VERSION 5.7 ;
  NOWIREEXTENSIONATPIN ON ;
  DIVIDERCHAR "/" ;
  BUSBITCHARS "[]" ;
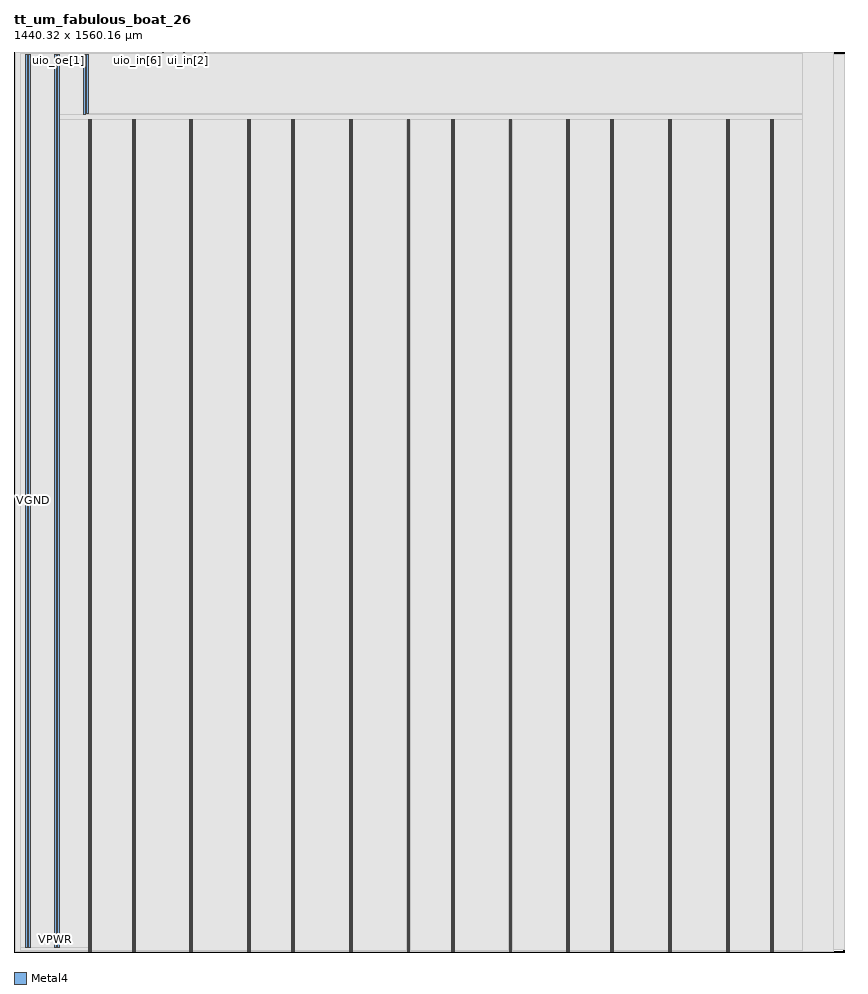
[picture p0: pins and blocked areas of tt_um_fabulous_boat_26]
MACRO tt_um_fabulous_boat_26
  CLASS BLOCK ;
  FOREIGN tt_um_fabulous_boat_26 ;
  ORIGIN 0.000 0.000 ;
  SIZE 1440.320 BY 1560.160 ;
  PIN VGND
    DIRECTION INOUT ;
    USE GROUND ;
    PORT
      LAYER Metal4 ;
        RECT 132.580 1368.760 134.180 1443.240 ;
    END
    PORT
      LAYER Metal4 ;
        RECT 132.580 1110.040 134.180 1368.760 ;
    END
    PORT
      LAYER Metal4 ;
        RECT 132.580 851.320 134.180 1110.040 ;
    END
    PORT
      LAYER Metal4 ;
        RECT 132.580 592.600 134.180 851.320 ;
    END
    PORT
      LAYER Metal4 ;
        RECT 132.580 333.880 134.180 592.600 ;
    END
    PORT
      LAYER Metal4 ;
        RECT 132.580 75.160 134.180 333.880 ;
    END
    PORT
      LAYER Metal4 ;
        RECT 132.580 0.680 134.180 75.160 ;
    END
    PORT
      LAYER Metal4 ;
        RECT 208.180 1368.760 209.780 1443.240 ;
    END
    PORT
      LAYER Metal4 ;
        RECT 308.180 1368.760 309.780 1443.240 ;
    END
    PORT
      LAYER Metal4 ;
        RECT 408.180 1368.760 409.780 1443.240 ;
    END
    PORT
      LAYER Metal4 ;
        RECT 208.180 1110.040 209.780 1368.760 ;
    END
    PORT
      LAYER Metal4 ;
        RECT 308.180 1110.040 309.780 1368.760 ;
    END
    PORT
      LAYER Metal4 ;
        RECT 408.180 1110.040 409.780 1368.760 ;
    END
    PORT
      LAYER Metal4 ;
        RECT 208.180 851.320 209.780 1110.040 ;
    END
    PORT
      LAYER Metal4 ;
        RECT 308.180 851.320 309.780 1110.040 ;
    END
    PORT
      LAYER Metal4 ;
        RECT 408.180 851.320 409.780 1110.040 ;
    END
    PORT
      LAYER Metal4 ;
        RECT 208.180 592.600 209.780 851.320 ;
    END
    PORT
      LAYER Metal4 ;
        RECT 308.180 592.600 309.780 851.320 ;
    END
    PORT
      LAYER Metal4 ;
        RECT 408.180 592.600 409.780 851.320 ;
    END
    PORT
      LAYER Metal4 ;
        RECT 208.180 333.880 209.780 592.600 ;
    END
    PORT
      LAYER Metal4 ;
        RECT 308.180 333.880 309.780 592.600 ;
    END
    PORT
      LAYER Metal4 ;
        RECT 408.180 333.880 409.780 592.600 ;
    END
    PORT
      LAYER Metal4 ;
        RECT 208.180 75.160 209.780 333.880 ;
    END
    PORT
      LAYER Metal4 ;
        RECT 308.180 75.160 309.780 333.880 ;
    END
    PORT
      LAYER Metal4 ;
        RECT 408.180 75.160 409.780 333.880 ;
    END
    PORT
      LAYER Metal4 ;
        RECT 208.180 0.680 209.780 75.160 ;
    END
    PORT
      LAYER Metal4 ;
        RECT 308.180 0.680 309.780 75.160 ;
    END
    PORT
      LAYER Metal4 ;
        RECT 408.180 0.680 409.780 75.160 ;
    END
    PORT
      LAYER Metal4 ;
        RECT 484.820 1368.760 486.420 1443.240 ;
    END
    PORT
      LAYER Metal4 ;
        RECT 584.820 1368.760 586.420 1443.240 ;
    END
    PORT
      LAYER Metal4 ;
        RECT 684.820 1368.760 686.420 1443.240 ;
    END
    PORT
      LAYER Metal4 ;
        RECT 484.820 1110.040 486.420 1368.760 ;
    END
    PORT
      LAYER Metal4 ;
        RECT 584.820 1110.040 586.420 1368.760 ;
    END
    PORT
      LAYER Metal4 ;
        RECT 684.820 1110.040 686.420 1368.760 ;
    END
    PORT
      LAYER Metal4 ;
        RECT 484.820 851.320 486.420 1110.040 ;
    END
    PORT
      LAYER Metal4 ;
        RECT 584.820 851.320 586.420 1110.040 ;
    END
    PORT
      LAYER Metal4 ;
        RECT 684.820 851.320 686.420 1110.040 ;
    END
    PORT
      LAYER Metal4 ;
        RECT 484.820 592.600 486.420 851.320 ;
    END
    PORT
      LAYER Metal4 ;
        RECT 584.820 592.600 586.420 851.320 ;
    END
    PORT
      LAYER Metal4 ;
        RECT 684.820 592.600 686.420 851.320 ;
    END
    PORT
      LAYER Metal4 ;
        RECT 484.820 333.880 486.420 592.600 ;
    END
    PORT
      LAYER Metal4 ;
        RECT 584.820 333.880 586.420 592.600 ;
    END
    PORT
      LAYER Metal4 ;
        RECT 684.820 333.880 686.420 592.600 ;
    END
    PORT
      LAYER Metal4 ;
        RECT 484.820 75.160 486.420 333.880 ;
    END
    PORT
      LAYER Metal4 ;
        RECT 584.820 75.160 586.420 333.880 ;
    END
    PORT
      LAYER Metal4 ;
        RECT 684.820 75.160 686.420 333.880 ;
    END
    PORT
      LAYER Metal4 ;
        RECT 484.820 0.680 486.420 75.160 ;
    END
    PORT
      LAYER Metal4 ;
        RECT 584.820 0.680 586.420 75.160 ;
    END
    PORT
      LAYER Metal4 ;
        RECT 684.820 0.680 686.420 75.160 ;
    END
    PORT
      LAYER Metal4 ;
        RECT 761.460 1368.760 763.060 1443.240 ;
    END
    PORT
      LAYER Metal4 ;
        RECT 861.460 1368.760 863.060 1443.240 ;
    END
    PORT
      LAYER Metal4 ;
        RECT 961.460 1368.760 963.060 1443.240 ;
    END
    PORT
      LAYER Metal4 ;
        RECT 761.460 1110.040 763.060 1368.760 ;
    END
    PORT
      LAYER Metal4 ;
        RECT 861.460 1110.040 863.060 1368.760 ;
    END
    PORT
      LAYER Metal4 ;
        RECT 961.460 1110.040 963.060 1368.760 ;
    END
    PORT
      LAYER Metal4 ;
        RECT 761.460 851.320 763.060 1110.040 ;
    END
    PORT
      LAYER Metal4 ;
        RECT 861.460 851.320 863.060 1110.040 ;
    END
    PORT
      LAYER Metal4 ;
        RECT 961.460 851.320 963.060 1110.040 ;
    END
    PORT
      LAYER Metal4 ;
        RECT 761.460 592.600 763.060 851.320 ;
    END
    PORT
      LAYER Metal4 ;
        RECT 861.460 592.600 863.060 851.320 ;
    END
    PORT
      LAYER Metal4 ;
        RECT 961.460 592.600 963.060 851.320 ;
    END
    PORT
      LAYER Metal4 ;
        RECT 761.460 333.880 763.060 592.600 ;
    END
    PORT
      LAYER Metal4 ;
        RECT 861.460 333.880 863.060 592.600 ;
    END
    PORT
      LAYER Metal4 ;
        RECT 961.460 333.880 963.060 592.600 ;
    END
    PORT
      LAYER Metal4 ;
        RECT 761.460 75.160 763.060 333.880 ;
    END
    PORT
      LAYER Metal4 ;
        RECT 861.460 75.160 863.060 333.880 ;
    END
    PORT
      LAYER Metal4 ;
        RECT 961.460 75.160 963.060 333.880 ;
    END
    PORT
      LAYER Metal4 ;
        RECT 761.460 0.680 763.060 75.160 ;
    END
    PORT
      LAYER Metal4 ;
        RECT 861.460 0.680 863.060 75.160 ;
    END
    PORT
      LAYER Metal4 ;
        RECT 961.460 0.680 963.060 75.160 ;
    END
    PORT
      LAYER Metal4 ;
        RECT 1038.100 1368.760 1039.700 1443.240 ;
    END
    PORT
      LAYER Metal4 ;
        RECT 1138.100 1368.760 1139.700 1443.240 ;
    END
    PORT
      LAYER Metal4 ;
        RECT 1238.100 1368.760 1239.700 1443.240 ;
    END
    PORT
      LAYER Metal4 ;
        RECT 1038.100 1110.040 1039.700 1368.760 ;
    END
    PORT
      LAYER Metal4 ;
        RECT 1138.100 1110.040 1139.700 1368.760 ;
    END
    PORT
      LAYER Metal4 ;
        RECT 1238.100 1110.040 1239.700 1368.760 ;
    END
    PORT
      LAYER Metal4 ;
        RECT 1038.100 851.320 1039.700 1110.040 ;
    END
    PORT
      LAYER Metal4 ;
        RECT 1138.100 851.320 1139.700 1110.040 ;
    END
    PORT
      LAYER Metal4 ;
        RECT 1238.100 851.320 1239.700 1110.040 ;
    END
    PORT
      LAYER Metal4 ;
        RECT 1038.100 592.600 1039.700 851.320 ;
    END
    PORT
      LAYER Metal4 ;
        RECT 1138.100 592.600 1139.700 851.320 ;
    END
    PORT
      LAYER Metal4 ;
        RECT 1238.100 592.600 1239.700 851.320 ;
    END
    PORT
      LAYER Metal4 ;
        RECT 1038.100 333.880 1039.700 592.600 ;
    END
    PORT
      LAYER Metal4 ;
        RECT 1138.100 333.880 1139.700 592.600 ;
    END
    PORT
      LAYER Metal4 ;
        RECT 1238.100 333.880 1239.700 592.600 ;
    END
    PORT
      LAYER Metal4 ;
        RECT 1038.100 75.160 1039.700 333.880 ;
    END
    PORT
      LAYER Metal4 ;
        RECT 1138.100 75.160 1139.700 333.880 ;
    END
    PORT
      LAYER Metal4 ;
        RECT 1238.100 75.160 1239.700 333.880 ;
    END
    PORT
      LAYER Metal4 ;
        RECT 1038.100 0.680 1039.700 75.160 ;
    END
    PORT
      LAYER Metal4 ;
        RECT 1138.100 0.680 1139.700 75.160 ;
    END
    PORT
      LAYER Metal4 ;
        RECT 1238.100 0.680 1239.700 75.160 ;
    END
    PORT
      LAYER Metal4 ;
        RECT 1314.740 1368.760 1316.340 1443.240 ;
    END
    PORT
      LAYER Metal4 ;
        RECT 1314.740 1110.040 1316.340 1368.760 ;
    END
    PORT
      LAYER Metal4 ;
        RECT 1314.740 851.320 1316.340 1110.040 ;
    END
    PORT
      LAYER Metal4 ;
        RECT 1314.740 592.600 1316.340 851.320 ;
    END
    PORT
      LAYER Metal4 ;
        RECT 1314.740 333.880 1316.340 592.600 ;
    END
    PORT
      LAYER Metal4 ;
        RECT 1314.740 75.160 1316.340 333.880 ;
    END
    PORT
      LAYER Metal4 ;
        RECT 1314.740 0.680 1316.340 75.160 ;
    END
    PORT
      LAYER Metal4 ;
        RECT 25.540 7.540 28.740 1556.540 ;
    END
    PORT
      LAYER Metal4 ;
        RECT 75.540 7.540 78.740 1556.540 ;
    END
    PORT
      LAYER Metal4 ;
        RECT 125.540 1453.800 128.740 1556.540 ;
    END
  END VGND
  PIN VPWR
    DIRECTION INOUT ;
    USE POWER ;
    PORT
      LAYER Metal4 ;
        RECT 129.280 1368.760 130.880 1443.240 ;
    END
    PORT
      LAYER Metal4 ;
        RECT 129.280 1110.040 130.880 1368.760 ;
    END
    PORT
      LAYER Metal4 ;
        RECT 129.280 851.320 130.880 1110.040 ;
    END
    PORT
      LAYER Metal4 ;
        RECT 129.280 592.600 130.880 851.320 ;
    END
    PORT
      LAYER Metal4 ;
        RECT 129.280 333.880 130.880 592.600 ;
    END
    PORT
      LAYER Metal4 ;
        RECT 129.280 75.160 130.880 333.880 ;
    END
    PORT
      LAYER Metal4 ;
        RECT 129.280 0.680 130.880 75.160 ;
    END
    PORT
      LAYER Metal4 ;
        RECT 204.880 1368.760 206.480 1443.240 ;
    END
    PORT
      LAYER Metal4 ;
        RECT 304.880 1368.760 306.480 1443.240 ;
    END
    PORT
      LAYER Metal4 ;
        RECT 404.880 1368.760 406.480 1443.240 ;
    END
    PORT
      LAYER Metal4 ;
        RECT 204.880 1110.040 206.480 1368.760 ;
    END
    PORT
      LAYER Metal4 ;
        RECT 304.880 1110.040 306.480 1368.760 ;
    END
    PORT
      LAYER Metal4 ;
        RECT 404.880 1110.040 406.480 1368.760 ;
    END
    PORT
      LAYER Metal4 ;
        RECT 204.880 851.320 206.480 1110.040 ;
    END
    PORT
      LAYER Metal4 ;
        RECT 304.880 851.320 306.480 1110.040 ;
    END
    PORT
      LAYER Metal4 ;
        RECT 404.880 851.320 406.480 1110.040 ;
    END
    PORT
      LAYER Metal4 ;
        RECT 204.880 592.600 206.480 851.320 ;
    END
    PORT
      LAYER Metal4 ;
        RECT 304.880 592.600 306.480 851.320 ;
    END
    PORT
      LAYER Metal4 ;
        RECT 404.880 592.600 406.480 851.320 ;
    END
    PORT
      LAYER Metal4 ;
        RECT 204.880 333.880 206.480 592.600 ;
    END
    PORT
      LAYER Metal4 ;
        RECT 304.880 333.880 306.480 592.600 ;
    END
    PORT
      LAYER Metal4 ;
        RECT 404.880 333.880 406.480 592.600 ;
    END
    PORT
      LAYER Metal4 ;
        RECT 204.880 75.160 206.480 333.880 ;
    END
    PORT
      LAYER Metal4 ;
        RECT 304.880 75.160 306.480 333.880 ;
    END
    PORT
      LAYER Metal4 ;
        RECT 404.880 75.160 406.480 333.880 ;
    END
    PORT
      LAYER Metal4 ;
        RECT 204.880 0.680 206.480 75.160 ;
    END
    PORT
      LAYER Metal4 ;
        RECT 304.880 0.680 306.480 75.160 ;
    END
    PORT
      LAYER Metal4 ;
        RECT 404.880 0.680 406.480 75.160 ;
    END
    PORT
      LAYER Metal4 ;
        RECT 481.520 1368.760 483.120 1443.240 ;
    END
    PORT
      LAYER Metal4 ;
        RECT 581.520 1368.760 583.120 1443.240 ;
    END
    PORT
      LAYER Metal4 ;
        RECT 681.520 1368.760 683.120 1443.240 ;
    END
    PORT
      LAYER Metal4 ;
        RECT 481.520 1110.040 483.120 1368.760 ;
    END
    PORT
      LAYER Metal4 ;
        RECT 581.520 1110.040 583.120 1368.760 ;
    END
    PORT
      LAYER Metal4 ;
        RECT 681.520 1110.040 683.120 1368.760 ;
    END
    PORT
      LAYER Metal4 ;
        RECT 481.520 851.320 483.120 1110.040 ;
    END
    PORT
      LAYER Metal4 ;
        RECT 581.520 851.320 583.120 1110.040 ;
    END
    PORT
      LAYER Metal4 ;
        RECT 681.520 851.320 683.120 1110.040 ;
    END
    PORT
      LAYER Metal4 ;
        RECT 481.520 592.600 483.120 851.320 ;
    END
    PORT
      LAYER Metal4 ;
        RECT 581.520 592.600 583.120 851.320 ;
    END
    PORT
      LAYER Metal4 ;
        RECT 681.520 592.600 683.120 851.320 ;
    END
    PORT
      LAYER Metal4 ;
        RECT 481.520 333.880 483.120 592.600 ;
    END
    PORT
      LAYER Metal4 ;
        RECT 581.520 333.880 583.120 592.600 ;
    END
    PORT
      LAYER Metal4 ;
        RECT 681.520 333.880 683.120 592.600 ;
    END
    PORT
      LAYER Metal4 ;
        RECT 481.520 75.160 483.120 333.880 ;
    END
    PORT
      LAYER Metal4 ;
        RECT 581.520 75.160 583.120 333.880 ;
    END
    PORT
      LAYER Metal4 ;
        RECT 681.520 75.160 683.120 333.880 ;
    END
    PORT
      LAYER Metal4 ;
        RECT 481.520 0.680 483.120 75.160 ;
    END
    PORT
      LAYER Metal4 ;
        RECT 581.520 0.680 583.120 75.160 ;
    END
    PORT
      LAYER Metal4 ;
        RECT 681.520 0.680 683.120 75.160 ;
    END
    PORT
      LAYER Metal4 ;
        RECT 758.160 1368.760 759.760 1443.240 ;
    END
    PORT
      LAYER Metal4 ;
        RECT 858.160 1368.760 859.760 1443.240 ;
    END
    PORT
      LAYER Metal4 ;
        RECT 958.160 1368.760 959.760 1443.240 ;
    END
    PORT
      LAYER Metal4 ;
        RECT 758.160 1110.040 759.760 1368.760 ;
    END
    PORT
      LAYER Metal4 ;
        RECT 858.160 1110.040 859.760 1368.760 ;
    END
    PORT
      LAYER Metal4 ;
        RECT 958.160 1110.040 959.760 1368.760 ;
    END
    PORT
      LAYER Metal4 ;
        RECT 758.160 851.320 759.760 1110.040 ;
    END
    PORT
      LAYER Metal4 ;
        RECT 858.160 851.320 859.760 1110.040 ;
    END
    PORT
      LAYER Metal4 ;
        RECT 958.160 851.320 959.760 1110.040 ;
    END
    PORT
      LAYER Metal4 ;
        RECT 758.160 592.600 759.760 851.320 ;
    END
    PORT
      LAYER Metal4 ;
        RECT 858.160 592.600 859.760 851.320 ;
    END
    PORT
      LAYER Metal4 ;
        RECT 958.160 592.600 959.760 851.320 ;
    END
    PORT
      LAYER Metal4 ;
        RECT 758.160 333.880 759.760 592.600 ;
    END
    PORT
      LAYER Metal4 ;
        RECT 858.160 333.880 859.760 592.600 ;
    END
    PORT
      LAYER Metal4 ;
        RECT 958.160 333.880 959.760 592.600 ;
    END
    PORT
      LAYER Metal4 ;
        RECT 758.160 75.160 759.760 333.880 ;
    END
    PORT
      LAYER Metal4 ;
        RECT 858.160 75.160 859.760 333.880 ;
    END
    PORT
      LAYER Metal4 ;
        RECT 958.160 75.160 959.760 333.880 ;
    END
    PORT
      LAYER Metal4 ;
        RECT 758.160 0.680 759.760 75.160 ;
    END
    PORT
      LAYER Metal4 ;
        RECT 858.160 0.680 859.760 75.160 ;
    END
    PORT
      LAYER Metal4 ;
        RECT 958.160 0.680 959.760 75.160 ;
    END
    PORT
      LAYER Metal4 ;
        RECT 1034.800 1368.760 1036.400 1443.240 ;
    END
    PORT
      LAYER Metal4 ;
        RECT 1134.800 1368.760 1136.400 1443.240 ;
    END
    PORT
      LAYER Metal4 ;
        RECT 1234.800 1368.760 1236.400 1443.240 ;
    END
    PORT
      LAYER Metal4 ;
        RECT 1034.800 1110.040 1036.400 1368.760 ;
    END
    PORT
      LAYER Metal4 ;
        RECT 1134.800 1110.040 1136.400 1368.760 ;
    END
    PORT
      LAYER Metal4 ;
        RECT 1234.800 1110.040 1236.400 1368.760 ;
    END
    PORT
      LAYER Metal4 ;
        RECT 1034.800 851.320 1036.400 1110.040 ;
    END
    PORT
      LAYER Metal4 ;
        RECT 1134.800 851.320 1136.400 1110.040 ;
    END
    PORT
      LAYER Metal4 ;
        RECT 1234.800 851.320 1236.400 1110.040 ;
    END
    PORT
      LAYER Metal4 ;
        RECT 1034.800 592.600 1036.400 851.320 ;
    END
    PORT
      LAYER Metal4 ;
        RECT 1134.800 592.600 1136.400 851.320 ;
    END
    PORT
      LAYER Metal4 ;
        RECT 1234.800 592.600 1236.400 851.320 ;
    END
    PORT
      LAYER Metal4 ;
        RECT 1034.800 333.880 1036.400 592.600 ;
    END
    PORT
      LAYER Metal4 ;
        RECT 1134.800 333.880 1136.400 592.600 ;
    END
    PORT
      LAYER Metal4 ;
        RECT 1234.800 333.880 1236.400 592.600 ;
    END
    PORT
      LAYER Metal4 ;
        RECT 1034.800 75.160 1036.400 333.880 ;
    END
    PORT
      LAYER Metal4 ;
        RECT 1134.800 75.160 1136.400 333.880 ;
    END
    PORT
      LAYER Metal4 ;
        RECT 1234.800 75.160 1236.400 333.880 ;
    END
    PORT
      LAYER Metal4 ;
        RECT 1034.800 0.680 1036.400 75.160 ;
    END
    PORT
      LAYER Metal4 ;
        RECT 1134.800 0.680 1136.400 75.160 ;
    END
    PORT
      LAYER Metal4 ;
        RECT 1234.800 0.680 1236.400 75.160 ;
    END
    PORT
      LAYER Metal4 ;
        RECT 1311.440 1368.760 1313.040 1443.240 ;
    END
    PORT
      LAYER Metal4 ;
        RECT 1311.440 1110.040 1313.040 1368.760 ;
    END
    PORT
      LAYER Metal4 ;
        RECT 1311.440 851.320 1313.040 1110.040 ;
    END
    PORT
      LAYER Metal4 ;
        RECT 1311.440 592.600 1313.040 851.320 ;
    END
    PORT
      LAYER Metal4 ;
        RECT 1311.440 333.880 1313.040 592.600 ;
    END
    PORT
      LAYER Metal4 ;
        RECT 1311.440 75.160 1313.040 333.880 ;
    END
    PORT
      LAYER Metal4 ;
        RECT 1311.440 0.680 1313.040 75.160 ;
    END
    PORT
      LAYER Metal4 ;
        RECT 20.640 7.540 23.840 1556.540 ;
    END
    PORT
      LAYER Metal4 ;
        RECT 70.640 7.540 73.840 1556.540 ;
    END
    PORT
      LAYER Metal4 ;
        RECT 120.640 1452.310 123.840 1556.540 ;
    END
  END VPWR
  PIN clk
    DIRECTION INPUT ;
    USE SIGNAL ;
    ANTENNAGATEAREA 4.704000 ;
    ANTENNADIFFAREA 0.877000 ;
    PORT
      LAYER Metal4 ;
        RECT 331.090 1559.160 331.390 1560.160 ;
    END
  END clk
  PIN ena
    DIRECTION INPUT ;
    USE SIGNAL ;
    PORT
      LAYER Metal4 ;
        RECT 338.370 1559.160 338.670 1560.160 ;
    END
  END ena
  PIN rst_n
    DIRECTION INPUT ;
    USE SIGNAL ;
    ANTENNAGATEAREA 0.666400 ;
    ANTENNADIFFAREA 0.438500 ;
    PORT
      LAYER Metal4 ;
        RECT 323.810 1559.160 324.110 1560.160 ;
    END
  END rst_n
  PIN ui_in[0]
    DIRECTION INPUT ;
    USE SIGNAL ;
    ANTENNAGATEAREA 0.666400 ;
    ANTENNADIFFAREA 0.438500 ;
    PORT
      LAYER Metal4 ;
        RECT 316.530 1559.160 316.830 1560.160 ;
    END
  END ui_in[0]
  PIN ui_in[1]
    DIRECTION INPUT ;
    USE SIGNAL ;
    ANTENNAGATEAREA 0.666400 ;
    ANTENNADIFFAREA 0.438500 ;
    PORT
      LAYER Metal4 ;
        RECT 309.250 1559.160 309.550 1560.160 ;
    END
  END ui_in[1]
  PIN ui_in[2]
    DIRECTION INPUT ;
    USE SIGNAL ;
    ANTENNAGATEAREA 1.764000 ;
    ANTENNADIFFAREA 0.438500 ;
    PORT
      LAYER Metal4 ;
        RECT 301.970 1559.160 302.270 1560.160 ;
    END
  END ui_in[2]
  PIN ui_in[3]
    DIRECTION INPUT ;
    USE SIGNAL ;
    ANTENNAGATEAREA 1.764000 ;
    ANTENNADIFFAREA 0.438500 ;
    PORT
      LAYER Metal4 ;
        RECT 294.690 1559.160 294.990 1560.160 ;
    END
  END ui_in[3]
  PIN ui_in[4]
    DIRECTION INPUT ;
    USE SIGNAL ;
    ANTENNAGATEAREA 1.764000 ;
    ANTENNADIFFAREA 0.438500 ;
    PORT
      LAYER Metal4 ;
        RECT 287.410 1559.160 287.710 1560.160 ;
    END
  END ui_in[4]
  PIN ui_in[5]
    DIRECTION INPUT ;
    USE SIGNAL ;
    ANTENNAGATEAREA 1.764000 ;
    ANTENNADIFFAREA 0.438500 ;
    PORT
      LAYER Metal4 ;
        RECT 280.130 1559.160 280.430 1560.160 ;
    END
  END ui_in[5]
  PIN ui_in[6]
    DIRECTION INPUT ;
    USE SIGNAL ;
    ANTENNAGATEAREA 1.764000 ;
    ANTENNADIFFAREA 0.438500 ;
    PORT
      LAYER Metal4 ;
        RECT 272.850 1559.160 273.150 1560.160 ;
    END
  END ui_in[6]
  PIN ui_in[7]
    DIRECTION INPUT ;
    USE SIGNAL ;
    ANTENNAGATEAREA 1.764000 ;
    ANTENNADIFFAREA 0.438500 ;
    PORT
      LAYER Metal4 ;
        RECT 265.570 1559.160 265.870 1560.160 ;
    END
  END ui_in[7]
  PIN uio_in[0]
    DIRECTION INPUT ;
    USE SIGNAL ;
    ANTENNAGATEAREA 1.332800 ;
    ANTENNADIFFAREA 0.438500 ;
    PORT
      LAYER Metal4 ;
        RECT 258.290 1559.160 258.590 1560.160 ;
    END
  END uio_in[0]
  PIN uio_in[1]
    DIRECTION INPUT ;
    USE SIGNAL ;
    ANTENNAGATEAREA 1.332800 ;
    ANTENNADIFFAREA 0.438500 ;
    PORT
      LAYER Metal4 ;
        RECT 251.010 1559.160 251.310 1560.160 ;
    END
  END uio_in[1]
  PIN uio_in[2]
    DIRECTION INPUT ;
    USE SIGNAL ;
    ANTENNAGATEAREA 1.332800 ;
    ANTENNADIFFAREA 0.438500 ;
    PORT
      LAYER Metal4 ;
        RECT 243.730 1559.160 244.030 1560.160 ;
    END
  END uio_in[2]
  PIN uio_in[3]
    DIRECTION INPUT ;
    USE SIGNAL ;
    ANTENNAGATEAREA 1.332800 ;
    ANTENNADIFFAREA 0.438500 ;
    PORT
      LAYER Metal4 ;
        RECT 236.450 1559.160 236.750 1560.160 ;
    END
  END uio_in[3]
  PIN uio_in[4]
    DIRECTION INPUT ;
    USE SIGNAL ;
    ANTENNAGATEAREA 1.332800 ;
    ANTENNADIFFAREA 0.438500 ;
    PORT
      LAYER Metal4 ;
        RECT 229.170 1559.160 229.470 1560.160 ;
    END
  END uio_in[4]
  PIN uio_in[5]
    DIRECTION INPUT ;
    USE SIGNAL ;
    ANTENNAGATEAREA 1.332800 ;
    ANTENNADIFFAREA 0.438500 ;
    PORT
      LAYER Metal4 ;
        RECT 221.890 1559.160 222.190 1560.160 ;
    END
  END uio_in[5]
  PIN uio_in[6]
    DIRECTION INPUT ;
    USE SIGNAL ;
    ANTENNAGATEAREA 1.332800 ;
    ANTENNADIFFAREA 0.438500 ;
    PORT
      LAYER Metal4 ;
        RECT 214.610 1559.160 214.910 1560.160 ;
    END
  END uio_in[6]
  PIN uio_in[7]
    DIRECTION INPUT ;
    USE SIGNAL ;
    ANTENNAGATEAREA 1.332800 ;
    ANTENNADIFFAREA 0.438500 ;
    PORT
      LAYER Metal4 ;
        RECT 207.330 1559.160 207.630 1560.160 ;
    END
  END uio_in[7]
  PIN uio_oe[0]
    DIRECTION OUTPUT ;
    USE SIGNAL ;
    ANTENNADIFFAREA 1.676100 ;
    PORT
      LAYER Metal4 ;
        RECT 83.570 1559.160 83.870 1560.160 ;
    END
  END uio_oe[0]
  PIN uio_oe[1]
    DIRECTION OUTPUT ;
    USE SIGNAL ;
    ANTENNADIFFAREA 1.676100 ;
    PORT
      LAYER Metal4 ;
        RECT 76.290 1559.160 76.590 1560.160 ;
    END
  END uio_oe[1]
  PIN uio_oe[2]
    DIRECTION OUTPUT ;
    USE SIGNAL ;
    ANTENNADIFFAREA 1.676100 ;
    PORT
      LAYER Metal4 ;
        RECT 69.010 1559.160 69.310 1560.160 ;
    END
  END uio_oe[2]
  PIN uio_oe[3]
    DIRECTION OUTPUT ;
    USE SIGNAL ;
    ANTENNADIFFAREA 1.676100 ;
    PORT
      LAYER Metal4 ;
        RECT 61.730 1559.160 62.030 1560.160 ;
    END
  END uio_oe[3]
  PIN uio_oe[4]
    DIRECTION OUTPUT ;
    USE SIGNAL ;
    ANTENNADIFFAREA 1.676100 ;
    PORT
      LAYER Metal4 ;
        RECT 54.450 1559.160 54.750 1560.160 ;
    END
  END uio_oe[4]
  PIN uio_oe[5]
    DIRECTION OUTPUT ;
    USE SIGNAL ;
    ANTENNADIFFAREA 1.676100 ;
    PORT
      LAYER Metal4 ;
        RECT 47.170 1559.160 47.470 1560.160 ;
    END
  END uio_oe[5]
  PIN uio_oe[6]
    DIRECTION OUTPUT ;
    USE SIGNAL ;
    ANTENNADIFFAREA 1.676100 ;
    PORT
      LAYER Metal4 ;
        RECT 39.890 1559.160 40.190 1560.160 ;
    END
  END uio_oe[6]
  PIN uio_oe[7]
    DIRECTION OUTPUT ;
    USE SIGNAL ;
    ANTENNADIFFAREA 1.676100 ;
    PORT
      LAYER Metal4 ;
        RECT 32.610 1559.160 32.910 1560.160 ;
    END
  END uio_oe[7]
  PIN uio_out[0]
    DIRECTION OUTPUT ;
    USE SIGNAL ;
    ANTENNADIFFAREA 1.676100 ;
    PORT
      LAYER Metal4 ;
        RECT 141.810 1559.160 142.110 1560.160 ;
    END
  END uio_out[0]
  PIN uio_out[1]
    DIRECTION OUTPUT ;
    USE SIGNAL ;
    ANTENNADIFFAREA 1.676100 ;
    PORT
      LAYER Metal4 ;
        RECT 134.530 1559.160 134.830 1560.160 ;
    END
  END uio_out[1]
  PIN uio_out[2]
    DIRECTION OUTPUT ;
    USE SIGNAL ;
    ANTENNADIFFAREA 1.676100 ;
    PORT
      LAYER Metal4 ;
        RECT 127.250 1559.160 127.550 1560.160 ;
    END
  END uio_out[2]
  PIN uio_out[3]
    DIRECTION OUTPUT ;
    USE SIGNAL ;
    ANTENNADIFFAREA 1.676100 ;
    PORT
      LAYER Metal4 ;
        RECT 119.970 1559.160 120.270 1560.160 ;
    END
  END uio_out[3]
  PIN uio_out[4]
    DIRECTION OUTPUT ;
    USE SIGNAL ;
    ANTENNADIFFAREA 1.676100 ;
    PORT
      LAYER Metal4 ;
        RECT 112.690 1559.160 112.990 1560.160 ;
    END
  END uio_out[4]
  PIN uio_out[5]
    DIRECTION OUTPUT ;
    USE SIGNAL ;
    ANTENNADIFFAREA 1.676100 ;
    PORT
      LAYER Metal4 ;
        RECT 105.410 1559.160 105.710 1560.160 ;
    END
  END uio_out[5]
  PIN uio_out[6]
    DIRECTION OUTPUT ;
    USE SIGNAL ;
    ANTENNADIFFAREA 1.676100 ;
    PORT
      LAYER Metal4 ;
        RECT 98.130 1559.160 98.430 1560.160 ;
    END
  END uio_out[6]
  PIN uio_out[7]
    DIRECTION OUTPUT ;
    USE SIGNAL ;
    ANTENNADIFFAREA 1.676100 ;
    PORT
      LAYER Metal4 ;
        RECT 90.850 1559.160 91.150 1560.160 ;
    END
  END uio_out[7]
  PIN uo_out[0]
    DIRECTION OUTPUT ;
    USE SIGNAL ;
    ANTENNADIFFAREA 4.806500 ;
    PORT
      LAYER Metal4 ;
        RECT 200.050 1559.160 200.350 1560.160 ;
    END
  END uo_out[0]
  PIN uo_out[1]
    DIRECTION OUTPUT ;
    USE SIGNAL ;
    ANTENNADIFFAREA 4.806500 ;
    PORT
      LAYER Metal4 ;
        RECT 192.770 1559.160 193.070 1560.160 ;
    END
  END uo_out[1]
  PIN uo_out[2]
    DIRECTION OUTPUT ;
    USE SIGNAL ;
    ANTENNADIFFAREA 4.806500 ;
    PORT
      LAYER Metal4 ;
        RECT 185.490 1559.160 185.790 1560.160 ;
    END
  END uo_out[2]
  PIN uo_out[3]
    DIRECTION OUTPUT ;
    USE SIGNAL ;
    ANTENNADIFFAREA 4.806500 ;
    PORT
      LAYER Metal4 ;
        RECT 178.210 1559.160 178.510 1560.160 ;
    END
  END uo_out[3]
  PIN uo_out[4]
    DIRECTION OUTPUT ;
    USE SIGNAL ;
    ANTENNADIFFAREA 4.806500 ;
    PORT
      LAYER Metal4 ;
        RECT 170.930 1559.160 171.230 1560.160 ;
    END
  END uo_out[4]
  PIN uo_out[5]
    DIRECTION OUTPUT ;
    USE SIGNAL ;
    ANTENNADIFFAREA 4.806500 ;
    PORT
      LAYER Metal4 ;
        RECT 163.650 1559.160 163.950 1560.160 ;
    END
  END uo_out[5]
  PIN uo_out[6]
    DIRECTION OUTPUT ;
    USE SIGNAL ;
    ANTENNADIFFAREA 4.806500 ;
    PORT
      LAYER Metal4 ;
        RECT 156.370 1559.160 156.670 1560.160 ;
    END
  END uo_out[6]
  PIN uo_out[7]
    DIRECTION OUTPUT ;
    USE SIGNAL ;
    ANTENNADIFFAREA 4.806500 ;
    PORT
      LAYER Metal4 ;
        RECT 149.090 1559.160 149.390 1560.160 ;
    END
  END uo_out[7]
  OBS
      LAYER Nwell ;
        RECT 1.810 1554.090 1440.190 1556.670 ;
      LAYER Pwell ;
        RECT 1.810 1550.550 1440.190 1554.090 ;
      LAYER Nwell ;
        RECT 1.810 1546.250 1440.190 1550.550 ;
      LAYER Pwell ;
        RECT 1.810 1542.710 1440.190 1546.250 ;
      LAYER Nwell ;
        RECT 1.810 1538.410 1440.190 1542.710 ;
      LAYER Pwell ;
        RECT 1.810 1534.870 1440.190 1538.410 ;
      LAYER Nwell ;
        RECT 1.810 1530.570 1440.190 1534.870 ;
      LAYER Pwell ;
        RECT 1.810 1527.030 1440.190 1530.570 ;
      LAYER Nwell ;
        RECT 1.810 1522.730 1440.190 1527.030 ;
      LAYER Pwell ;
        RECT 1.810 1519.190 1440.190 1522.730 ;
      LAYER Nwell ;
        RECT 1.810 1514.890 1440.190 1519.190 ;
      LAYER Pwell ;
        RECT 1.810 1511.350 1440.190 1514.890 ;
      LAYER Nwell ;
        RECT 1.810 1507.050 1440.190 1511.350 ;
      LAYER Pwell ;
        RECT 1.810 1503.510 1440.190 1507.050 ;
      LAYER Nwell ;
        RECT 1.810 1499.210 1440.190 1503.510 ;
      LAYER Pwell ;
        RECT 1.810 1497.010 1440.190 1499.210 ;
        RECT 1.810 1495.670 1329.870 1497.010 ;
      LAYER Nwell ;
        RECT 1329.870 1495.670 1440.190 1497.010 ;
        RECT 1.810 1491.370 1440.190 1495.670 ;
      LAYER Pwell ;
        RECT 1.810 1487.830 1329.870 1491.370 ;
      LAYER Nwell ;
        RECT 1329.870 1487.830 1440.190 1491.370 ;
        RECT 1.810 1483.530 1440.190 1487.830 ;
      LAYER Pwell ;
        RECT 1.810 1479.990 1329.870 1483.530 ;
      LAYER Nwell ;
        RECT 1329.870 1479.990 1440.190 1483.530 ;
        RECT 1.810 1475.690 1440.190 1479.990 ;
      LAYER Pwell ;
        RECT 1.810 1472.150 1329.870 1475.690 ;
      LAYER Nwell ;
        RECT 1329.870 1472.150 1440.190 1475.690 ;
        RECT 1.810 1467.850 1440.190 1472.150 ;
      LAYER Pwell ;
        RECT 1.810 1464.310 1329.870 1467.850 ;
      LAYER Nwell ;
        RECT 1329.870 1464.310 1440.190 1467.850 ;
        RECT 1.810 1460.010 1440.190 1464.310 ;
      LAYER Pwell ;
        RECT 1.810 1456.470 1329.870 1460.010 ;
      LAYER Nwell ;
        RECT 1329.870 1456.470 1440.190 1460.010 ;
        RECT 1.810 1452.170 1440.190 1456.470 ;
      LAYER Pwell ;
        RECT 1.810 1449.970 1329.870 1452.170 ;
      LAYER Nwell ;
        RECT 1329.870 1449.970 1440.190 1452.170 ;
      LAYER Pwell ;
        RECT 1.810 1448.630 106.270 1449.970 ;
      LAYER Nwell ;
        RECT 106.270 1448.630 1440.190 1449.970 ;
        RECT 1.810 1444.330 1440.190 1448.630 ;
      LAYER Pwell ;
        RECT 1.810 1440.790 106.270 1444.330 ;
      LAYER Nwell ;
        RECT 106.270 1440.790 1440.190 1444.330 ;
        RECT 1.810 1436.490 1440.190 1440.790 ;
      LAYER Pwell ;
        RECT 1.810 1432.950 106.270 1436.490 ;
      LAYER Nwell ;
        RECT 106.270 1432.950 1440.190 1436.490 ;
        RECT 1.810 1428.650 1440.190 1432.950 ;
      LAYER Pwell ;
        RECT 1.810 1425.110 106.270 1428.650 ;
      LAYER Nwell ;
        RECT 106.270 1425.110 1440.190 1428.650 ;
        RECT 1.810 1420.810 1440.190 1425.110 ;
      LAYER Pwell ;
        RECT 1.810 1417.270 106.270 1420.810 ;
      LAYER Nwell ;
        RECT 106.270 1417.270 1440.190 1420.810 ;
        RECT 1.810 1412.970 1440.190 1417.270 ;
      LAYER Pwell ;
        RECT 1.810 1409.430 106.270 1412.970 ;
      LAYER Nwell ;
        RECT 106.270 1409.430 1440.190 1412.970 ;
        RECT 1.810 1405.130 1440.190 1409.430 ;
      LAYER Pwell ;
        RECT 1.810 1401.590 106.270 1405.130 ;
      LAYER Nwell ;
        RECT 106.270 1401.590 1440.190 1405.130 ;
        RECT 1.810 1397.290 1440.190 1401.590 ;
      LAYER Pwell ;
        RECT 1.810 1393.750 106.270 1397.290 ;
      LAYER Nwell ;
        RECT 106.270 1393.750 1440.190 1397.290 ;
        RECT 1.810 1389.450 1440.190 1393.750 ;
      LAYER Pwell ;
        RECT 1.810 1385.910 106.270 1389.450 ;
      LAYER Nwell ;
        RECT 106.270 1385.910 1440.190 1389.450 ;
        RECT 1.810 1381.610 1440.190 1385.910 ;
      LAYER Pwell ;
        RECT 1.810 1378.070 106.270 1381.610 ;
      LAYER Nwell ;
        RECT 106.270 1378.070 1440.190 1381.610 ;
        RECT 1.810 1373.770 1440.190 1378.070 ;
      LAYER Pwell ;
        RECT 1.810 1370.230 106.270 1373.770 ;
      LAYER Nwell ;
        RECT 106.270 1370.230 1440.190 1373.770 ;
        RECT 1.810 1365.930 1440.190 1370.230 ;
      LAYER Pwell ;
        RECT 1.810 1362.390 106.270 1365.930 ;
      LAYER Nwell ;
        RECT 106.270 1362.390 1440.190 1365.930 ;
        RECT 1.810 1358.090 1440.190 1362.390 ;
      LAYER Pwell ;
        RECT 1.810 1354.550 106.270 1358.090 ;
      LAYER Nwell ;
        RECT 106.270 1354.550 1440.190 1358.090 ;
        RECT 1.810 1350.250 1440.190 1354.550 ;
      LAYER Pwell ;
        RECT 1.810 1346.710 106.270 1350.250 ;
      LAYER Nwell ;
        RECT 106.270 1346.710 1440.190 1350.250 ;
        RECT 1.810 1342.410 1440.190 1346.710 ;
      LAYER Pwell ;
        RECT 1.810 1338.870 106.270 1342.410 ;
      LAYER Nwell ;
        RECT 106.270 1338.870 1440.190 1342.410 ;
        RECT 1.810 1334.570 1440.190 1338.870 ;
      LAYER Pwell ;
        RECT 1.810 1331.030 106.270 1334.570 ;
      LAYER Nwell ;
        RECT 106.270 1331.030 1440.190 1334.570 ;
        RECT 1.810 1326.730 1440.190 1331.030 ;
      LAYER Pwell ;
        RECT 1.810 1323.190 106.270 1326.730 ;
      LAYER Nwell ;
        RECT 106.270 1323.190 1440.190 1326.730 ;
        RECT 1.810 1318.890 1440.190 1323.190 ;
      LAYER Pwell ;
        RECT 1.810 1315.350 106.270 1318.890 ;
      LAYER Nwell ;
        RECT 106.270 1315.350 1440.190 1318.890 ;
        RECT 1.810 1311.050 1440.190 1315.350 ;
      LAYER Pwell ;
        RECT 1.810 1307.510 106.270 1311.050 ;
      LAYER Nwell ;
        RECT 106.270 1307.510 1440.190 1311.050 ;
        RECT 1.810 1303.210 1440.190 1307.510 ;
      LAYER Pwell ;
        RECT 1.810 1299.670 106.270 1303.210 ;
      LAYER Nwell ;
        RECT 106.270 1299.670 1440.190 1303.210 ;
        RECT 1.810 1295.370 1440.190 1299.670 ;
      LAYER Pwell ;
        RECT 1.810 1291.830 106.270 1295.370 ;
      LAYER Nwell ;
        RECT 106.270 1291.830 1440.190 1295.370 ;
        RECT 1.810 1287.530 1440.190 1291.830 ;
      LAYER Pwell ;
        RECT 1.810 1283.990 106.270 1287.530 ;
      LAYER Nwell ;
        RECT 106.270 1283.990 1440.190 1287.530 ;
        RECT 1.810 1279.690 1440.190 1283.990 ;
      LAYER Pwell ;
        RECT 1.810 1276.150 106.270 1279.690 ;
      LAYER Nwell ;
        RECT 106.270 1276.150 1440.190 1279.690 ;
        RECT 1.810 1271.850 1440.190 1276.150 ;
      LAYER Pwell ;
        RECT 1.810 1268.310 106.270 1271.850 ;
      LAYER Nwell ;
        RECT 106.270 1268.310 1440.190 1271.850 ;
        RECT 1.810 1264.010 1440.190 1268.310 ;
      LAYER Pwell ;
        RECT 1.810 1260.470 106.270 1264.010 ;
      LAYER Nwell ;
        RECT 106.270 1260.470 1440.190 1264.010 ;
        RECT 1.810 1256.170 1440.190 1260.470 ;
      LAYER Pwell ;
        RECT 1.810 1252.630 106.270 1256.170 ;
      LAYER Nwell ;
        RECT 106.270 1252.630 1440.190 1256.170 ;
        RECT 1.810 1248.330 1440.190 1252.630 ;
      LAYER Pwell ;
        RECT 1.810 1244.790 106.270 1248.330 ;
      LAYER Nwell ;
        RECT 106.270 1244.790 1440.190 1248.330 ;
        RECT 1.810 1240.490 1440.190 1244.790 ;
      LAYER Pwell ;
        RECT 1.810 1236.950 106.270 1240.490 ;
      LAYER Nwell ;
        RECT 106.270 1236.950 1440.190 1240.490 ;
        RECT 1.810 1232.650 1440.190 1236.950 ;
      LAYER Pwell ;
        RECT 1.810 1229.110 106.270 1232.650 ;
      LAYER Nwell ;
        RECT 106.270 1229.110 1440.190 1232.650 ;
        RECT 1.810 1224.810 1440.190 1229.110 ;
      LAYER Pwell ;
        RECT 1.810 1221.270 106.270 1224.810 ;
      LAYER Nwell ;
        RECT 106.270 1221.270 1440.190 1224.810 ;
        RECT 1.810 1216.970 1440.190 1221.270 ;
      LAYER Pwell ;
        RECT 1.810 1213.430 106.270 1216.970 ;
      LAYER Nwell ;
        RECT 106.270 1213.430 1440.190 1216.970 ;
        RECT 1.810 1209.130 1440.190 1213.430 ;
      LAYER Pwell ;
        RECT 1.810 1205.590 106.270 1209.130 ;
      LAYER Nwell ;
        RECT 106.270 1205.590 1440.190 1209.130 ;
        RECT 1.810 1201.290 1440.190 1205.590 ;
      LAYER Pwell ;
        RECT 1.810 1197.750 106.270 1201.290 ;
      LAYER Nwell ;
        RECT 106.270 1197.750 1440.190 1201.290 ;
        RECT 1.810 1193.450 1440.190 1197.750 ;
      LAYER Pwell ;
        RECT 1.810 1189.910 106.270 1193.450 ;
      LAYER Nwell ;
        RECT 106.270 1189.910 1440.190 1193.450 ;
        RECT 1.810 1185.610 1440.190 1189.910 ;
      LAYER Pwell ;
        RECT 1.810 1182.070 106.270 1185.610 ;
      LAYER Nwell ;
        RECT 106.270 1182.070 1440.190 1185.610 ;
        RECT 1.810 1177.770 1440.190 1182.070 ;
      LAYER Pwell ;
        RECT 1.810 1174.230 106.270 1177.770 ;
      LAYER Nwell ;
        RECT 106.270 1174.230 1440.190 1177.770 ;
        RECT 1.810 1169.930 1440.190 1174.230 ;
      LAYER Pwell ;
        RECT 1.810 1166.390 106.270 1169.930 ;
      LAYER Nwell ;
        RECT 106.270 1166.390 1440.190 1169.930 ;
        RECT 1.810 1162.090 1440.190 1166.390 ;
      LAYER Pwell ;
        RECT 1.810 1158.550 106.270 1162.090 ;
      LAYER Nwell ;
        RECT 106.270 1158.550 1440.190 1162.090 ;
        RECT 1.810 1154.250 1440.190 1158.550 ;
      LAYER Pwell ;
        RECT 1.810 1150.710 106.270 1154.250 ;
      LAYER Nwell ;
        RECT 106.270 1150.710 1440.190 1154.250 ;
        RECT 1.810 1146.410 1440.190 1150.710 ;
      LAYER Pwell ;
        RECT 1.810 1142.870 106.270 1146.410 ;
      LAYER Nwell ;
        RECT 106.270 1142.870 1440.190 1146.410 ;
        RECT 1.810 1138.570 1440.190 1142.870 ;
      LAYER Pwell ;
        RECT 1.810 1135.030 106.270 1138.570 ;
      LAYER Nwell ;
        RECT 106.270 1135.030 1440.190 1138.570 ;
        RECT 1.810 1130.730 1440.190 1135.030 ;
      LAYER Pwell ;
        RECT 1.810 1127.190 106.270 1130.730 ;
      LAYER Nwell ;
        RECT 106.270 1127.190 1440.190 1130.730 ;
        RECT 1.810 1122.890 1440.190 1127.190 ;
      LAYER Pwell ;
        RECT 1.810 1119.350 106.270 1122.890 ;
      LAYER Nwell ;
        RECT 106.270 1119.350 1440.190 1122.890 ;
        RECT 1.810 1115.050 1440.190 1119.350 ;
      LAYER Pwell ;
        RECT 1.810 1111.510 106.270 1115.050 ;
      LAYER Nwell ;
        RECT 106.270 1111.510 1440.190 1115.050 ;
        RECT 1.810 1107.210 1440.190 1111.510 ;
      LAYER Pwell ;
        RECT 1.810 1103.670 106.270 1107.210 ;
      LAYER Nwell ;
        RECT 106.270 1103.670 1440.190 1107.210 ;
        RECT 1.810 1099.370 1440.190 1103.670 ;
      LAYER Pwell ;
        RECT 1.810 1095.830 106.270 1099.370 ;
      LAYER Nwell ;
        RECT 106.270 1095.830 1440.190 1099.370 ;
        RECT 1.810 1091.530 1440.190 1095.830 ;
      LAYER Pwell ;
        RECT 1.810 1087.990 106.270 1091.530 ;
      LAYER Nwell ;
        RECT 106.270 1087.990 1440.190 1091.530 ;
        RECT 1.810 1083.690 1440.190 1087.990 ;
      LAYER Pwell ;
        RECT 1.810 1080.150 106.270 1083.690 ;
      LAYER Nwell ;
        RECT 106.270 1080.150 1440.190 1083.690 ;
        RECT 1.810 1075.850 1440.190 1080.150 ;
      LAYER Pwell ;
        RECT 1.810 1072.310 106.270 1075.850 ;
      LAYER Nwell ;
        RECT 106.270 1072.310 1440.190 1075.850 ;
        RECT 1.810 1068.010 1440.190 1072.310 ;
      LAYER Pwell ;
        RECT 1.810 1064.470 106.270 1068.010 ;
      LAYER Nwell ;
        RECT 106.270 1064.470 1440.190 1068.010 ;
        RECT 1.810 1060.170 1440.190 1064.470 ;
      LAYER Pwell ;
        RECT 1.810 1056.630 106.270 1060.170 ;
      LAYER Nwell ;
        RECT 106.270 1056.630 1440.190 1060.170 ;
        RECT 1.810 1052.330 1440.190 1056.630 ;
      LAYER Pwell ;
        RECT 1.810 1048.790 106.270 1052.330 ;
      LAYER Nwell ;
        RECT 106.270 1048.790 1440.190 1052.330 ;
        RECT 1.810 1044.490 1440.190 1048.790 ;
      LAYER Pwell ;
        RECT 1.810 1040.950 106.270 1044.490 ;
      LAYER Nwell ;
        RECT 106.270 1040.950 1440.190 1044.490 ;
        RECT 1.810 1036.650 1440.190 1040.950 ;
      LAYER Pwell ;
        RECT 1.810 1033.110 106.270 1036.650 ;
      LAYER Nwell ;
        RECT 106.270 1033.110 1440.190 1036.650 ;
        RECT 1.810 1028.810 1440.190 1033.110 ;
      LAYER Pwell ;
        RECT 1.810 1025.270 106.270 1028.810 ;
      LAYER Nwell ;
        RECT 106.270 1025.270 1440.190 1028.810 ;
        RECT 1.810 1020.970 1440.190 1025.270 ;
      LAYER Pwell ;
        RECT 1.810 1017.430 106.270 1020.970 ;
      LAYER Nwell ;
        RECT 106.270 1017.430 1440.190 1020.970 ;
        RECT 1.810 1013.130 1440.190 1017.430 ;
      LAYER Pwell ;
        RECT 1.810 1009.590 106.270 1013.130 ;
      LAYER Nwell ;
        RECT 106.270 1009.590 1440.190 1013.130 ;
        RECT 1.810 1005.290 1440.190 1009.590 ;
      LAYER Pwell ;
        RECT 1.810 1001.750 106.270 1005.290 ;
      LAYER Nwell ;
        RECT 106.270 1001.750 1440.190 1005.290 ;
        RECT 1.810 997.450 1440.190 1001.750 ;
      LAYER Pwell ;
        RECT 1.810 993.910 106.270 997.450 ;
      LAYER Nwell ;
        RECT 106.270 993.910 1440.190 997.450 ;
        RECT 1.810 989.610 1440.190 993.910 ;
      LAYER Pwell ;
        RECT 1.810 986.070 106.270 989.610 ;
      LAYER Nwell ;
        RECT 106.270 986.070 1440.190 989.610 ;
        RECT 1.810 981.770 1440.190 986.070 ;
      LAYER Pwell ;
        RECT 1.810 978.230 106.270 981.770 ;
      LAYER Nwell ;
        RECT 106.270 978.230 1440.190 981.770 ;
        RECT 1.810 973.930 1440.190 978.230 ;
      LAYER Pwell ;
        RECT 1.810 970.390 106.270 973.930 ;
      LAYER Nwell ;
        RECT 106.270 970.390 1440.190 973.930 ;
        RECT 1.810 966.090 1440.190 970.390 ;
      LAYER Pwell ;
        RECT 1.810 962.550 106.270 966.090 ;
      LAYER Nwell ;
        RECT 106.270 962.550 1440.190 966.090 ;
        RECT 1.810 958.250 1440.190 962.550 ;
      LAYER Pwell ;
        RECT 1.810 954.710 106.270 958.250 ;
      LAYER Nwell ;
        RECT 106.270 954.710 1440.190 958.250 ;
        RECT 1.810 950.410 1440.190 954.710 ;
      LAYER Pwell ;
        RECT 1.810 946.870 106.270 950.410 ;
      LAYER Nwell ;
        RECT 106.270 946.870 1440.190 950.410 ;
        RECT 1.810 942.570 1440.190 946.870 ;
      LAYER Pwell ;
        RECT 1.810 939.030 106.270 942.570 ;
      LAYER Nwell ;
        RECT 106.270 939.030 1440.190 942.570 ;
        RECT 1.810 934.730 1440.190 939.030 ;
      LAYER Pwell ;
        RECT 1.810 931.190 106.270 934.730 ;
      LAYER Nwell ;
        RECT 106.270 931.190 1440.190 934.730 ;
        RECT 1.810 926.890 1440.190 931.190 ;
      LAYER Pwell ;
        RECT 1.810 923.350 106.270 926.890 ;
      LAYER Nwell ;
        RECT 106.270 923.350 1440.190 926.890 ;
        RECT 1.810 919.050 1440.190 923.350 ;
      LAYER Pwell ;
        RECT 1.810 915.510 106.270 919.050 ;
      LAYER Nwell ;
        RECT 106.270 915.510 1440.190 919.050 ;
        RECT 1.810 911.210 1440.190 915.510 ;
      LAYER Pwell ;
        RECT 1.810 907.670 106.270 911.210 ;
      LAYER Nwell ;
        RECT 106.270 907.670 1440.190 911.210 ;
        RECT 1.810 903.370 1440.190 907.670 ;
      LAYER Pwell ;
        RECT 1.810 899.830 106.270 903.370 ;
      LAYER Nwell ;
        RECT 106.270 899.830 1440.190 903.370 ;
        RECT 1.810 895.530 1440.190 899.830 ;
      LAYER Pwell ;
        RECT 1.810 891.990 106.270 895.530 ;
      LAYER Nwell ;
        RECT 106.270 891.990 1440.190 895.530 ;
        RECT 1.810 887.690 1440.190 891.990 ;
      LAYER Pwell ;
        RECT 1.810 884.150 106.270 887.690 ;
      LAYER Nwell ;
        RECT 106.270 884.150 1440.190 887.690 ;
        RECT 1.810 879.850 1440.190 884.150 ;
      LAYER Pwell ;
        RECT 1.810 876.310 106.270 879.850 ;
      LAYER Nwell ;
        RECT 106.270 876.310 1440.190 879.850 ;
        RECT 1.810 872.010 1440.190 876.310 ;
      LAYER Pwell ;
        RECT 1.810 868.470 106.270 872.010 ;
      LAYER Nwell ;
        RECT 106.270 868.470 1440.190 872.010 ;
        RECT 1.810 864.170 1440.190 868.470 ;
      LAYER Pwell ;
        RECT 1.810 860.630 106.270 864.170 ;
      LAYER Nwell ;
        RECT 106.270 860.630 1440.190 864.170 ;
        RECT 1.810 856.330 1440.190 860.630 ;
      LAYER Pwell ;
        RECT 1.810 852.790 106.270 856.330 ;
      LAYER Nwell ;
        RECT 106.270 852.790 1440.190 856.330 ;
        RECT 1.810 848.490 1440.190 852.790 ;
      LAYER Pwell ;
        RECT 1.810 844.950 106.270 848.490 ;
      LAYER Nwell ;
        RECT 106.270 844.950 1440.190 848.490 ;
        RECT 1.810 840.650 1440.190 844.950 ;
      LAYER Pwell ;
        RECT 1.810 837.110 106.270 840.650 ;
      LAYER Nwell ;
        RECT 106.270 837.110 1440.190 840.650 ;
        RECT 1.810 832.810 1440.190 837.110 ;
      LAYER Pwell ;
        RECT 1.810 829.270 106.270 832.810 ;
      LAYER Nwell ;
        RECT 106.270 829.270 1440.190 832.810 ;
        RECT 1.810 824.970 1440.190 829.270 ;
      LAYER Pwell ;
        RECT 1.810 821.430 106.270 824.970 ;
      LAYER Nwell ;
        RECT 106.270 821.430 1440.190 824.970 ;
        RECT 1.810 817.130 1440.190 821.430 ;
      LAYER Pwell ;
        RECT 1.810 813.590 106.270 817.130 ;
      LAYER Nwell ;
        RECT 106.270 813.590 1440.190 817.130 ;
        RECT 1.810 809.290 1440.190 813.590 ;
      LAYER Pwell ;
        RECT 1.810 805.750 106.270 809.290 ;
      LAYER Nwell ;
        RECT 106.270 805.750 1440.190 809.290 ;
        RECT 1.810 801.450 1440.190 805.750 ;
      LAYER Pwell ;
        RECT 1.810 797.910 106.270 801.450 ;
      LAYER Nwell ;
        RECT 106.270 797.910 1440.190 801.450 ;
        RECT 1.810 793.610 1440.190 797.910 ;
      LAYER Pwell ;
        RECT 1.810 790.070 106.270 793.610 ;
      LAYER Nwell ;
        RECT 106.270 790.070 1440.190 793.610 ;
        RECT 1.810 785.770 1440.190 790.070 ;
      LAYER Pwell ;
        RECT 1.810 782.230 106.270 785.770 ;
      LAYER Nwell ;
        RECT 106.270 782.230 1440.190 785.770 ;
        RECT 1.810 777.930 1440.190 782.230 ;
      LAYER Pwell ;
        RECT 1.810 774.390 106.270 777.930 ;
      LAYER Nwell ;
        RECT 106.270 774.390 1440.190 777.930 ;
        RECT 1.810 770.090 1440.190 774.390 ;
      LAYER Pwell ;
        RECT 1.810 766.550 106.270 770.090 ;
      LAYER Nwell ;
        RECT 106.270 766.550 1440.190 770.090 ;
        RECT 1.810 762.250 1440.190 766.550 ;
      LAYER Pwell ;
        RECT 1.810 758.710 106.270 762.250 ;
      LAYER Nwell ;
        RECT 106.270 758.710 1440.190 762.250 ;
        RECT 1.810 754.410 1440.190 758.710 ;
      LAYER Pwell ;
        RECT 1.810 750.870 106.270 754.410 ;
      LAYER Nwell ;
        RECT 106.270 750.870 1440.190 754.410 ;
        RECT 1.810 746.570 1440.190 750.870 ;
      LAYER Pwell ;
        RECT 1.810 743.030 106.270 746.570 ;
      LAYER Nwell ;
        RECT 106.270 743.030 1440.190 746.570 ;
        RECT 1.810 738.730 1440.190 743.030 ;
      LAYER Pwell ;
        RECT 1.810 735.190 106.270 738.730 ;
      LAYER Nwell ;
        RECT 106.270 735.190 1440.190 738.730 ;
        RECT 1.810 730.890 1440.190 735.190 ;
      LAYER Pwell ;
        RECT 1.810 727.350 106.270 730.890 ;
      LAYER Nwell ;
        RECT 106.270 727.350 1440.190 730.890 ;
        RECT 1.810 723.050 1440.190 727.350 ;
      LAYER Pwell ;
        RECT 1.810 719.510 106.270 723.050 ;
      LAYER Nwell ;
        RECT 106.270 719.510 1440.190 723.050 ;
        RECT 1.810 715.210 1440.190 719.510 ;
      LAYER Pwell ;
        RECT 1.810 711.670 106.270 715.210 ;
      LAYER Nwell ;
        RECT 106.270 711.670 1440.190 715.210 ;
        RECT 1.810 707.370 1440.190 711.670 ;
      LAYER Pwell ;
        RECT 1.810 703.830 106.270 707.370 ;
      LAYER Nwell ;
        RECT 106.270 703.830 1440.190 707.370 ;
        RECT 1.810 699.530 1440.190 703.830 ;
      LAYER Pwell ;
        RECT 1.810 695.990 106.270 699.530 ;
      LAYER Nwell ;
        RECT 106.270 695.990 1440.190 699.530 ;
        RECT 1.810 691.690 1440.190 695.990 ;
      LAYER Pwell ;
        RECT 1.810 688.150 106.270 691.690 ;
      LAYER Nwell ;
        RECT 106.270 688.150 1440.190 691.690 ;
        RECT 1.810 683.850 1440.190 688.150 ;
      LAYER Pwell ;
        RECT 1.810 680.310 106.270 683.850 ;
      LAYER Nwell ;
        RECT 106.270 680.310 1440.190 683.850 ;
        RECT 1.810 676.010 1440.190 680.310 ;
      LAYER Pwell ;
        RECT 1.810 672.470 106.270 676.010 ;
      LAYER Nwell ;
        RECT 106.270 672.470 1440.190 676.010 ;
        RECT 1.810 668.170 1440.190 672.470 ;
      LAYER Pwell ;
        RECT 1.810 664.630 106.270 668.170 ;
      LAYER Nwell ;
        RECT 106.270 664.630 1440.190 668.170 ;
        RECT 1.810 660.330 1440.190 664.630 ;
      LAYER Pwell ;
        RECT 1.810 656.790 106.270 660.330 ;
      LAYER Nwell ;
        RECT 106.270 656.790 1440.190 660.330 ;
        RECT 1.810 652.490 1440.190 656.790 ;
      LAYER Pwell ;
        RECT 1.810 648.950 106.270 652.490 ;
      LAYER Nwell ;
        RECT 106.270 648.950 1440.190 652.490 ;
        RECT 1.810 644.650 1440.190 648.950 ;
      LAYER Pwell ;
        RECT 1.810 641.110 106.270 644.650 ;
      LAYER Nwell ;
        RECT 106.270 641.110 1440.190 644.650 ;
        RECT 1.810 636.810 1440.190 641.110 ;
      LAYER Pwell ;
        RECT 1.810 633.270 106.270 636.810 ;
      LAYER Nwell ;
        RECT 106.270 633.270 1440.190 636.810 ;
        RECT 1.810 628.970 1440.190 633.270 ;
      LAYER Pwell ;
        RECT 1.810 625.430 106.270 628.970 ;
      LAYER Nwell ;
        RECT 106.270 625.430 1440.190 628.970 ;
        RECT 1.810 621.130 1440.190 625.430 ;
      LAYER Pwell ;
        RECT 1.810 617.590 106.270 621.130 ;
      LAYER Nwell ;
        RECT 106.270 617.590 1440.190 621.130 ;
        RECT 1.810 613.290 1440.190 617.590 ;
      LAYER Pwell ;
        RECT 1.810 609.750 106.270 613.290 ;
      LAYER Nwell ;
        RECT 106.270 609.750 1440.190 613.290 ;
        RECT 1.810 605.450 1440.190 609.750 ;
      LAYER Pwell ;
        RECT 1.810 601.910 106.270 605.450 ;
      LAYER Nwell ;
        RECT 106.270 601.910 1440.190 605.450 ;
        RECT 1.810 597.610 1440.190 601.910 ;
      LAYER Pwell ;
        RECT 1.810 594.070 106.270 597.610 ;
      LAYER Nwell ;
        RECT 106.270 594.070 1440.190 597.610 ;
        RECT 1.810 589.770 1440.190 594.070 ;
      LAYER Pwell ;
        RECT 1.810 586.230 106.270 589.770 ;
      LAYER Nwell ;
        RECT 106.270 586.230 1440.190 589.770 ;
        RECT 1.810 581.930 1440.190 586.230 ;
      LAYER Pwell ;
        RECT 1.810 578.390 106.270 581.930 ;
      LAYER Nwell ;
        RECT 106.270 578.390 1440.190 581.930 ;
        RECT 1.810 574.090 1440.190 578.390 ;
      LAYER Pwell ;
        RECT 1.810 570.550 106.270 574.090 ;
      LAYER Nwell ;
        RECT 106.270 570.550 1440.190 574.090 ;
        RECT 1.810 566.250 1440.190 570.550 ;
      LAYER Pwell ;
        RECT 1.810 562.710 106.270 566.250 ;
      LAYER Nwell ;
        RECT 106.270 562.710 1440.190 566.250 ;
        RECT 1.810 558.410 1440.190 562.710 ;
      LAYER Pwell ;
        RECT 1.810 554.870 106.270 558.410 ;
      LAYER Nwell ;
        RECT 106.270 554.870 1440.190 558.410 ;
        RECT 1.810 550.570 1440.190 554.870 ;
      LAYER Pwell ;
        RECT 1.810 547.030 106.270 550.570 ;
      LAYER Nwell ;
        RECT 106.270 547.030 1440.190 550.570 ;
        RECT 1.810 542.730 1440.190 547.030 ;
      LAYER Pwell ;
        RECT 1.810 539.190 106.270 542.730 ;
      LAYER Nwell ;
        RECT 106.270 539.190 1440.190 542.730 ;
        RECT 1.810 534.890 1440.190 539.190 ;
      LAYER Pwell ;
        RECT 1.810 531.350 106.270 534.890 ;
      LAYER Nwell ;
        RECT 106.270 531.350 1440.190 534.890 ;
        RECT 1.810 527.050 1440.190 531.350 ;
      LAYER Pwell ;
        RECT 1.810 523.510 106.270 527.050 ;
      LAYER Nwell ;
        RECT 106.270 523.510 1440.190 527.050 ;
        RECT 1.810 519.210 1440.190 523.510 ;
      LAYER Pwell ;
        RECT 1.810 515.670 106.270 519.210 ;
      LAYER Nwell ;
        RECT 106.270 515.670 1440.190 519.210 ;
        RECT 1.810 511.370 1440.190 515.670 ;
      LAYER Pwell ;
        RECT 1.810 507.830 106.270 511.370 ;
      LAYER Nwell ;
        RECT 106.270 507.830 1440.190 511.370 ;
        RECT 1.810 503.530 1440.190 507.830 ;
      LAYER Pwell ;
        RECT 1.810 499.990 106.270 503.530 ;
      LAYER Nwell ;
        RECT 106.270 499.990 1440.190 503.530 ;
        RECT 1.810 495.690 1440.190 499.990 ;
      LAYER Pwell ;
        RECT 1.810 492.150 106.270 495.690 ;
      LAYER Nwell ;
        RECT 106.270 492.150 1440.190 495.690 ;
        RECT 1.810 487.850 1440.190 492.150 ;
      LAYER Pwell ;
        RECT 1.810 484.310 106.270 487.850 ;
      LAYER Nwell ;
        RECT 106.270 484.310 1440.190 487.850 ;
        RECT 1.810 480.010 1440.190 484.310 ;
      LAYER Pwell ;
        RECT 1.810 476.470 106.270 480.010 ;
      LAYER Nwell ;
        RECT 106.270 476.470 1440.190 480.010 ;
        RECT 1.810 472.170 1440.190 476.470 ;
      LAYER Pwell ;
        RECT 1.810 468.630 106.270 472.170 ;
      LAYER Nwell ;
        RECT 106.270 468.630 1440.190 472.170 ;
        RECT 1.810 464.330 1440.190 468.630 ;
      LAYER Pwell ;
        RECT 1.810 460.790 106.270 464.330 ;
      LAYER Nwell ;
        RECT 106.270 460.790 1440.190 464.330 ;
        RECT 1.810 456.490 1440.190 460.790 ;
      LAYER Pwell ;
        RECT 1.810 452.950 106.270 456.490 ;
      LAYER Nwell ;
        RECT 106.270 452.950 1440.190 456.490 ;
        RECT 1.810 448.650 1440.190 452.950 ;
      LAYER Pwell ;
        RECT 1.810 445.110 106.270 448.650 ;
      LAYER Nwell ;
        RECT 106.270 445.110 1440.190 448.650 ;
        RECT 1.810 440.810 1440.190 445.110 ;
      LAYER Pwell ;
        RECT 1.810 437.270 106.270 440.810 ;
      LAYER Nwell ;
        RECT 106.270 437.270 1440.190 440.810 ;
        RECT 1.810 432.970 1440.190 437.270 ;
      LAYER Pwell ;
        RECT 1.810 429.430 106.270 432.970 ;
      LAYER Nwell ;
        RECT 106.270 429.430 1440.190 432.970 ;
        RECT 1.810 425.130 1440.190 429.430 ;
      LAYER Pwell ;
        RECT 1.810 421.590 106.270 425.130 ;
      LAYER Nwell ;
        RECT 106.270 421.590 1440.190 425.130 ;
        RECT 1.810 417.290 1440.190 421.590 ;
      LAYER Pwell ;
        RECT 1.810 413.750 106.270 417.290 ;
      LAYER Nwell ;
        RECT 106.270 413.750 1440.190 417.290 ;
        RECT 1.810 409.450 1440.190 413.750 ;
      LAYER Pwell ;
        RECT 1.810 405.910 106.270 409.450 ;
      LAYER Nwell ;
        RECT 106.270 405.910 1440.190 409.450 ;
        RECT 1.810 401.610 1440.190 405.910 ;
      LAYER Pwell ;
        RECT 1.810 398.070 106.270 401.610 ;
      LAYER Nwell ;
        RECT 106.270 398.070 1440.190 401.610 ;
        RECT 1.810 393.770 1440.190 398.070 ;
      LAYER Pwell ;
        RECT 1.810 390.230 106.270 393.770 ;
      LAYER Nwell ;
        RECT 106.270 390.230 1440.190 393.770 ;
        RECT 1.810 385.930 1440.190 390.230 ;
      LAYER Pwell ;
        RECT 1.810 382.390 106.270 385.930 ;
      LAYER Nwell ;
        RECT 106.270 382.390 1440.190 385.930 ;
        RECT 1.810 378.090 1440.190 382.390 ;
      LAYER Pwell ;
        RECT 1.810 374.550 106.270 378.090 ;
      LAYER Nwell ;
        RECT 106.270 374.550 1440.190 378.090 ;
        RECT 1.810 370.250 1440.190 374.550 ;
      LAYER Pwell ;
        RECT 1.810 366.710 106.270 370.250 ;
      LAYER Nwell ;
        RECT 106.270 366.710 1440.190 370.250 ;
        RECT 1.810 362.410 1440.190 366.710 ;
      LAYER Pwell ;
        RECT 1.810 358.870 106.270 362.410 ;
      LAYER Nwell ;
        RECT 106.270 358.870 1440.190 362.410 ;
        RECT 1.810 354.570 1440.190 358.870 ;
      LAYER Pwell ;
        RECT 1.810 351.030 106.270 354.570 ;
      LAYER Nwell ;
        RECT 106.270 351.030 1440.190 354.570 ;
        RECT 1.810 346.730 1440.190 351.030 ;
      LAYER Pwell ;
        RECT 1.810 343.190 106.270 346.730 ;
      LAYER Nwell ;
        RECT 106.270 343.190 1440.190 346.730 ;
        RECT 1.810 338.890 1440.190 343.190 ;
      LAYER Pwell ;
        RECT 1.810 335.350 106.270 338.890 ;
      LAYER Nwell ;
        RECT 106.270 335.350 1440.190 338.890 ;
        RECT 1.810 331.050 1440.190 335.350 ;
      LAYER Pwell ;
        RECT 1.810 327.510 106.270 331.050 ;
      LAYER Nwell ;
        RECT 106.270 327.510 1440.190 331.050 ;
        RECT 1.810 323.210 1440.190 327.510 ;
      LAYER Pwell ;
        RECT 1.810 319.670 106.270 323.210 ;
      LAYER Nwell ;
        RECT 106.270 319.670 1440.190 323.210 ;
        RECT 1.810 315.370 1440.190 319.670 ;
      LAYER Pwell ;
        RECT 1.810 311.830 106.270 315.370 ;
      LAYER Nwell ;
        RECT 106.270 311.830 1440.190 315.370 ;
        RECT 1.810 307.530 1440.190 311.830 ;
      LAYER Pwell ;
        RECT 1.810 303.990 106.270 307.530 ;
      LAYER Nwell ;
        RECT 106.270 303.990 1440.190 307.530 ;
        RECT 1.810 299.690 1440.190 303.990 ;
      LAYER Pwell ;
        RECT 1.810 296.150 106.270 299.690 ;
      LAYER Nwell ;
        RECT 106.270 296.150 1440.190 299.690 ;
        RECT 1.810 291.850 1440.190 296.150 ;
      LAYER Pwell ;
        RECT 1.810 288.310 106.270 291.850 ;
      LAYER Nwell ;
        RECT 106.270 288.310 1440.190 291.850 ;
        RECT 1.810 284.010 1440.190 288.310 ;
      LAYER Pwell ;
        RECT 1.810 280.470 106.270 284.010 ;
      LAYER Nwell ;
        RECT 106.270 280.470 1440.190 284.010 ;
        RECT 1.810 276.170 1440.190 280.470 ;
      LAYER Pwell ;
        RECT 1.810 272.630 106.270 276.170 ;
      LAYER Nwell ;
        RECT 106.270 272.630 1440.190 276.170 ;
        RECT 1.810 268.330 1440.190 272.630 ;
      LAYER Pwell ;
        RECT 1.810 264.790 106.270 268.330 ;
      LAYER Nwell ;
        RECT 106.270 264.790 1440.190 268.330 ;
        RECT 1.810 260.490 1440.190 264.790 ;
      LAYER Pwell ;
        RECT 1.810 256.950 106.270 260.490 ;
      LAYER Nwell ;
        RECT 106.270 256.950 1440.190 260.490 ;
        RECT 1.810 252.650 1440.190 256.950 ;
      LAYER Pwell ;
        RECT 1.810 249.110 106.270 252.650 ;
      LAYER Nwell ;
        RECT 106.270 249.110 1440.190 252.650 ;
        RECT 1.810 244.810 1440.190 249.110 ;
      LAYER Pwell ;
        RECT 1.810 241.270 106.270 244.810 ;
      LAYER Nwell ;
        RECT 106.270 241.270 1440.190 244.810 ;
        RECT 1.810 236.970 1440.190 241.270 ;
      LAYER Pwell ;
        RECT 1.810 233.430 106.270 236.970 ;
      LAYER Nwell ;
        RECT 106.270 233.430 1440.190 236.970 ;
        RECT 1.810 229.130 1440.190 233.430 ;
      LAYER Pwell ;
        RECT 1.810 225.590 106.270 229.130 ;
      LAYER Nwell ;
        RECT 106.270 225.590 1440.190 229.130 ;
        RECT 1.810 221.290 1440.190 225.590 ;
      LAYER Pwell ;
        RECT 1.810 217.750 106.270 221.290 ;
      LAYER Nwell ;
        RECT 106.270 217.750 1440.190 221.290 ;
        RECT 1.810 213.450 1440.190 217.750 ;
      LAYER Pwell ;
        RECT 1.810 209.910 106.270 213.450 ;
      LAYER Nwell ;
        RECT 106.270 209.910 1440.190 213.450 ;
        RECT 1.810 205.610 1440.190 209.910 ;
      LAYER Pwell ;
        RECT 1.810 202.070 106.270 205.610 ;
      LAYER Nwell ;
        RECT 106.270 202.070 1440.190 205.610 ;
        RECT 1.810 197.770 1440.190 202.070 ;
      LAYER Pwell ;
        RECT 1.810 194.230 106.270 197.770 ;
      LAYER Nwell ;
        RECT 106.270 194.230 1440.190 197.770 ;
        RECT 1.810 189.930 1440.190 194.230 ;
      LAYER Pwell ;
        RECT 1.810 186.390 106.270 189.930 ;
      LAYER Nwell ;
        RECT 106.270 186.390 1440.190 189.930 ;
        RECT 1.810 182.090 1440.190 186.390 ;
      LAYER Pwell ;
        RECT 1.810 178.550 106.270 182.090 ;
      LAYER Nwell ;
        RECT 106.270 178.550 1440.190 182.090 ;
        RECT 1.810 174.250 1440.190 178.550 ;
      LAYER Pwell ;
        RECT 1.810 170.710 106.270 174.250 ;
      LAYER Nwell ;
        RECT 106.270 170.710 1440.190 174.250 ;
        RECT 1.810 166.410 1440.190 170.710 ;
      LAYER Pwell ;
        RECT 1.810 162.870 106.270 166.410 ;
      LAYER Nwell ;
        RECT 106.270 162.870 1440.190 166.410 ;
        RECT 1.810 158.570 1440.190 162.870 ;
      LAYER Pwell ;
        RECT 1.810 155.030 106.270 158.570 ;
      LAYER Nwell ;
        RECT 106.270 155.030 1440.190 158.570 ;
        RECT 1.810 150.730 1440.190 155.030 ;
      LAYER Pwell ;
        RECT 1.810 147.190 106.270 150.730 ;
      LAYER Nwell ;
        RECT 106.270 147.190 1440.190 150.730 ;
        RECT 1.810 142.890 1440.190 147.190 ;
      LAYER Pwell ;
        RECT 1.810 139.350 106.270 142.890 ;
      LAYER Nwell ;
        RECT 106.270 139.350 1440.190 142.890 ;
        RECT 1.810 135.050 1440.190 139.350 ;
      LAYER Pwell ;
        RECT 1.810 131.510 106.270 135.050 ;
      LAYER Nwell ;
        RECT 106.270 131.510 1440.190 135.050 ;
        RECT 1.810 127.210 1440.190 131.510 ;
      LAYER Pwell ;
        RECT 1.810 123.670 106.270 127.210 ;
      LAYER Nwell ;
        RECT 106.270 123.670 1440.190 127.210 ;
        RECT 1.810 119.370 1440.190 123.670 ;
      LAYER Pwell ;
        RECT 1.810 115.830 106.270 119.370 ;
      LAYER Nwell ;
        RECT 106.270 115.830 1440.190 119.370 ;
        RECT 1.810 111.530 1440.190 115.830 ;
      LAYER Pwell ;
        RECT 1.810 107.990 106.270 111.530 ;
      LAYER Nwell ;
        RECT 106.270 107.990 1440.190 111.530 ;
        RECT 1.810 103.690 1440.190 107.990 ;
      LAYER Pwell ;
        RECT 1.810 100.150 106.270 103.690 ;
      LAYER Nwell ;
        RECT 106.270 100.150 1440.190 103.690 ;
        RECT 1.810 95.850 1440.190 100.150 ;
      LAYER Pwell ;
        RECT 1.810 92.310 106.270 95.850 ;
      LAYER Nwell ;
        RECT 106.270 92.310 1440.190 95.850 ;
        RECT 1.810 88.010 1440.190 92.310 ;
      LAYER Pwell ;
        RECT 1.810 84.470 106.270 88.010 ;
      LAYER Nwell ;
        RECT 106.270 84.470 1440.190 88.010 ;
        RECT 1.810 80.170 1440.190 84.470 ;
      LAYER Pwell ;
        RECT 1.810 76.630 106.270 80.170 ;
      LAYER Nwell ;
        RECT 106.270 76.630 1440.190 80.170 ;
        RECT 1.810 72.330 1440.190 76.630 ;
      LAYER Pwell ;
        RECT 1.810 68.790 106.270 72.330 ;
      LAYER Nwell ;
        RECT 106.270 68.790 1440.190 72.330 ;
        RECT 1.810 64.490 1440.190 68.790 ;
      LAYER Pwell ;
        RECT 1.810 60.950 106.270 64.490 ;
      LAYER Nwell ;
        RECT 106.270 60.950 1440.190 64.490 ;
        RECT 1.810 56.650 1440.190 60.950 ;
      LAYER Pwell ;
        RECT 1.810 53.110 106.270 56.650 ;
      LAYER Nwell ;
        RECT 106.270 53.110 1440.190 56.650 ;
        RECT 1.810 48.810 1440.190 53.110 ;
      LAYER Pwell ;
        RECT 1.810 45.270 106.270 48.810 ;
      LAYER Nwell ;
        RECT 106.270 45.270 1440.190 48.810 ;
        RECT 1.810 40.970 1440.190 45.270 ;
      LAYER Pwell ;
        RECT 1.810 37.430 106.270 40.970 ;
      LAYER Nwell ;
        RECT 106.270 37.430 1440.190 40.970 ;
        RECT 1.810 33.130 1440.190 37.430 ;
      LAYER Pwell ;
        RECT 1.810 29.590 106.270 33.130 ;
      LAYER Nwell ;
        RECT 106.270 29.590 1440.190 33.130 ;
        RECT 1.810 25.290 1440.190 29.590 ;
      LAYER Pwell ;
        RECT 1.810 21.750 106.270 25.290 ;
      LAYER Nwell ;
        RECT 106.270 21.750 1440.190 25.290 ;
        RECT 1.810 17.450 1440.190 21.750 ;
      LAYER Pwell ;
        RECT 1.810 13.910 106.270 17.450 ;
      LAYER Nwell ;
        RECT 106.270 13.910 1440.190 17.450 ;
        RECT 1.810 9.610 1440.190 13.910 ;
      LAYER Pwell ;
        RECT 1.810 7.410 106.270 9.610 ;
      LAYER Nwell ;
        RECT 106.270 7.410 1440.190 9.610 ;
        RECT 1.810 4.170 1440.190 7.410 ;
      LAYER Metal1 ;
        RECT 2.240 4.300 1439.760 1556.540 ;
      LAYER Metal2 ;
        RECT 2.940 0.680 1420.580 1559.510 ;
      LAYER Metal3 ;
        RECT 2.890 1.380 1420.630 1559.460 ;
      LAYER Metal4 ;
        RECT 11.340 1558.860 32.310 1559.160 ;
        RECT 33.210 1558.860 39.590 1559.160 ;
        RECT 40.490 1558.860 46.870 1559.160 ;
        RECT 47.770 1558.860 54.150 1559.160 ;
        RECT 55.050 1558.860 61.430 1559.160 ;
        RECT 62.330 1558.860 68.710 1559.160 ;
        RECT 69.610 1558.860 75.990 1559.160 ;
        RECT 76.890 1558.860 83.270 1559.160 ;
        RECT 84.170 1558.860 90.550 1559.160 ;
        RECT 91.450 1558.860 97.830 1559.160 ;
        RECT 98.730 1558.860 105.110 1559.160 ;
        RECT 106.010 1558.860 112.390 1559.160 ;
        RECT 113.290 1558.860 119.670 1559.160 ;
        RECT 120.570 1558.860 126.950 1559.160 ;
        RECT 127.850 1558.860 134.230 1559.160 ;
        RECT 135.130 1558.860 141.510 1559.160 ;
        RECT 142.410 1558.860 148.790 1559.160 ;
        RECT 149.690 1558.860 156.070 1559.160 ;
        RECT 156.970 1558.860 163.350 1559.160 ;
        RECT 164.250 1558.860 170.630 1559.160 ;
        RECT 171.530 1558.860 177.910 1559.160 ;
        RECT 178.810 1558.860 185.190 1559.160 ;
        RECT 186.090 1558.860 192.470 1559.160 ;
        RECT 193.370 1558.860 199.750 1559.160 ;
        RECT 200.650 1558.860 207.030 1559.160 ;
        RECT 207.930 1558.860 214.310 1559.160 ;
        RECT 215.210 1558.860 221.590 1559.160 ;
        RECT 222.490 1558.860 228.870 1559.160 ;
        RECT 229.770 1558.860 236.150 1559.160 ;
        RECT 237.050 1558.860 243.430 1559.160 ;
        RECT 244.330 1558.860 250.710 1559.160 ;
        RECT 251.610 1558.860 257.990 1559.160 ;
        RECT 258.890 1558.860 265.270 1559.160 ;
        RECT 266.170 1558.860 272.550 1559.160 ;
        RECT 273.450 1558.860 279.830 1559.160 ;
        RECT 280.730 1558.860 287.110 1559.160 ;
        RECT 288.010 1558.860 294.390 1559.160 ;
        RECT 295.290 1558.860 301.670 1559.160 ;
        RECT 302.570 1558.860 308.950 1559.160 ;
        RECT 309.850 1558.860 316.230 1559.160 ;
        RECT 317.130 1558.860 323.510 1559.160 ;
        RECT 324.410 1558.860 330.790 1559.160 ;
        RECT 331.690 1558.860 338.070 1559.160 ;
        RECT 338.970 1558.860 1367.460 1559.160 ;
        RECT 11.340 1556.840 1367.460 1558.860 ;
        RECT 11.340 7.240 20.340 1556.840 ;
        RECT 24.140 7.240 25.240 1556.840 ;
        RECT 29.040 7.240 70.340 1556.840 ;
        RECT 74.140 7.240 75.240 1556.840 ;
        RECT 79.040 1452.010 120.340 1556.840 ;
        RECT 124.140 1453.500 125.240 1556.840 ;
        RECT 129.040 1453.500 1367.460 1556.840 ;
        RECT 124.140 1452.010 1367.460 1453.500 ;
        RECT 79.040 1443.540 1367.460 1452.010 ;
        RECT 79.040 7.240 128.980 1443.540 ;
        RECT 11.340 3.010 128.980 7.240 ;
        RECT 131.180 3.010 132.280 1443.540 ;
        RECT 134.480 3.010 204.580 1443.540 ;
        RECT 206.780 3.010 207.880 1443.540 ;
        RECT 210.080 3.010 304.580 1443.540 ;
        RECT 306.780 3.010 307.880 1443.540 ;
        RECT 310.080 3.010 404.580 1443.540 ;
        RECT 406.780 3.010 407.880 1443.540 ;
        RECT 410.080 3.010 481.220 1443.540 ;
        RECT 483.420 3.010 484.520 1443.540 ;
        RECT 486.720 3.010 581.220 1443.540 ;
        RECT 583.420 3.010 584.520 1443.540 ;
        RECT 586.720 3.010 681.220 1443.540 ;
        RECT 683.420 3.010 684.520 1443.540 ;
        RECT 686.720 3.010 757.860 1443.540 ;
        RECT 760.060 3.010 761.160 1443.540 ;
        RECT 763.360 3.010 857.860 1443.540 ;
        RECT 860.060 3.010 861.160 1443.540 ;
        RECT 863.360 3.010 957.860 1443.540 ;
        RECT 960.060 3.010 961.160 1443.540 ;
        RECT 963.360 3.010 1034.500 1443.540 ;
        RECT 1036.700 3.010 1037.800 1443.540 ;
        RECT 1040.000 3.010 1134.500 1443.540 ;
        RECT 1136.700 3.010 1137.800 1443.540 ;
        RECT 1140.000 3.010 1234.500 1443.540 ;
        RECT 1236.700 3.010 1237.800 1443.540 ;
        RECT 1240.000 3.010 1311.140 1443.540 ;
        RECT 1313.340 3.010 1314.440 1443.540 ;
        RECT 1316.640 3.010 1367.460 1443.540 ;
  END
END tt_um_fabulous_boat_26
END LIBRARY

